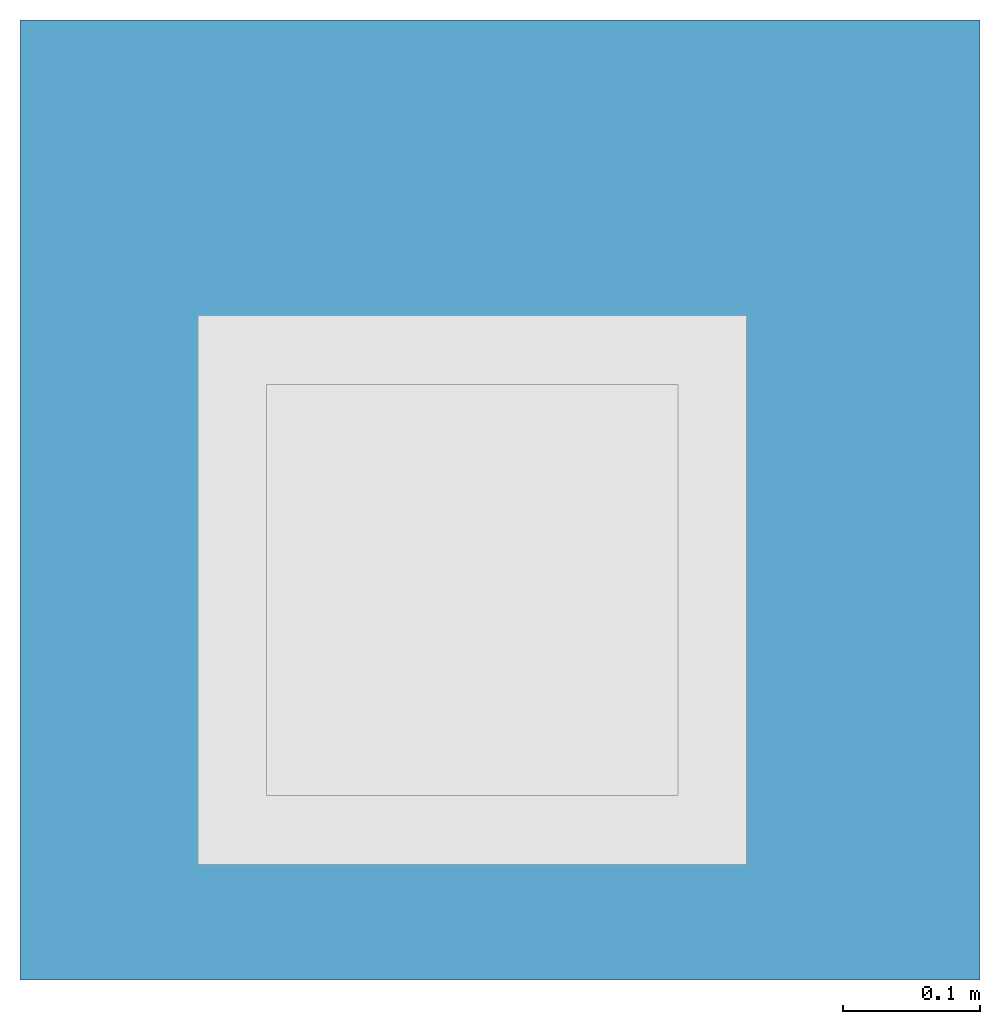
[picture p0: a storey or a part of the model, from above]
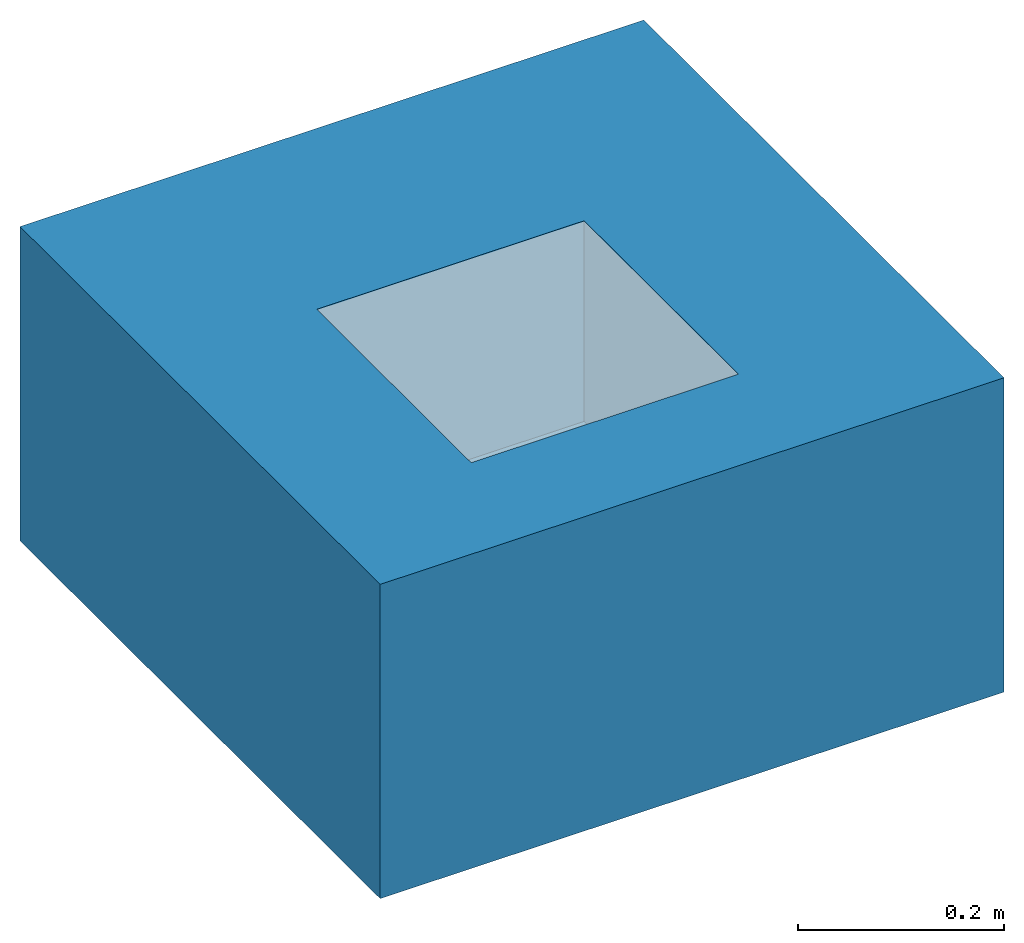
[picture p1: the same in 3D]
Properties of the parts of a building model (IFC2X3)

# File
Description: ViewDefinition [CoordinationView]
File name: Project Number
Time: 2014-10-13T17:47:48
Written by: The EXPRESS Data Manager Version 5.01.0100.02.64mod : 6 Jun 2012
Made in: 20130308_1515(x64) - Exporter 2014.0.2013.0308 - Default UI
Comment: STEP Physical File produced by: The EXPRESS Data Manager Version 5.01.0100.02.64mod : 6 Jun 2012 * Module: EDMstepFileFactory/EDMstandAlone * Creation date: Mon Oct 13 17:47:48 2014 * Host: IN-BLR-PC-0012 * Database: C:\Users\pponnur\AppData\Local\Temp\{98D3B113-D90C-4DA0-A6F4-5854EFEE299B}\ifc * Database version: 5507 * Database creation date: Mon Oct 13 17:47:47 2014 * Schema: IFC2X3 * Model: DataRepository.ifc * Model creation date: Mon Oct 13 17:47:48 2014 * Header model: DataRepository.ifc_HeaderModel * Header model creation date: Mon Oct 13 17:47:48 2014 * EDMuser: sdai-user * EDMgroup: sdai-group * License ID and type: 5605 : Permanent license. Expiry date: * EDMstepFileFactory options: 020000

# IfcProject, Project Number
LongName: Project Name; Phase: Project Status

# IfcSite, Default
RefLatitude: 42, 21, 30, 344238; RefLongitude: -71, -3, -35, -194702; RefElevation: 0 mm

# IfcBuilding
Pset_BuildingCommon - NumberOfStoreys: 1
Other - Client Name: Owner; Project Status: Project Status; Project Issue Date: Issue Date; Project Number: Project Number; Project Name: Project Name; Project Address: Enter address here

# IfcBuildingStorey, Level 1
LongName: Level 1; Elevation: 0 mm
Constraints - Elevation Base: Project Base Point; Elevation: 0 mm
Graphics - Symbol: Level Head - Circle: Level Head - Circle; Symbol at End 2 Default: yes; Symbol at End 1 Default: no; Color: 0; Line Pattern: Grid Line 1/2"; Line Weight: 1
Dimensions - Computation Height: 0 mm
Identity Data - Name: Level 1; Building Story: yes; Structural: no

# IfcFlowTerminal: 408061 Body / 408243 Top, ACO BD Gully 218 Telescopic - Thin Bed - Vertical Outlet with Location Flange - 300x300:408061 Body / 408243 Top:195708
In: Level 1
Material: Stainless Steel AISI 304, Rubber, Nitrile
Materials and Finishes - Material: Stainless Steel AISI 304
Construction - 408034 - 268 x 268mm - Mesh Grating - Slip Resistant - Stainless Steel 304: no; 408037 - 268 x 268mm - Ladder Grating - Slip Resistant - Stainless steel 304: no; 408035 - 268 x 268mm - Mesh Grating - Plain - Stainless Steel 304: no; 408222 - Silt Basket: yes; 408036 - 268 x 268mm - Quadrato Grating - Brushed - Stainless steel 304: no; 408045 - 268 x 268mm - Ladder Grating - Plain - Stainless Steel 304: no; 408039 - 268 x 268mm - Slot Cover - Plain - Stainless Steel 304: no; 408042 - 268 x 268mm - Volcano Grating - Slip Resistant - Stainless Steel 304: no; 408038 - 268 x 268mm - Ladder Grating - Plain - Stainless Steel 304: no; 408220 - Foul Air Trap & 408221 - Foul Air Trap Support Ring: yes; 408041 - 268 x 268mm - Arla Grating - Slip Resistant - Stainless Steel 304: no; 408040 - 268 x 268mm - HeelSafe Grating - Brushed - Stainless Steel 304: no
Mechanical - System Classification: Sanitary
Dimensions - Outlet Void Start: -238 mm; Floor Void End: -238 mm; FFL To Gully Top Height: 68 mm; Floor To Gully Height: 68 mm; Rasing Piece Height: 500 mm; Outlet Void End: -336 mm; Gully Outlet Radius: 55 mm; Gully Outlet Depth: 98 mm; Gully Outlet Diameter: 110 mm; Thin Bed Void Start: 0 mm; Thin Bed Void End: 2 mm
Other - Raising Piece Detail: no; 408209 - Raising Piece with Location Flange: no; Thin Bed Void: no; 110 mm Outlet: yes; 160 mm Outlet: no
Constraints - Level: Level: Level 1
Phasing - Phase Created: New Construction
Model Properties - Raising Piece Product Code 408209: NA; Product Code 408225: Friction Ring Installation Set - Nitrile; Product Code 408222: Silt Basket - Stainless Steel 304; Grating Product Code 408038: Load Class M125 (EN 1253) - Ladder Grating -Plain - Stainless steel 1.4301 (EN 10088) - 268 x 268 x 30mm; Grating Product Code 408042: Load Class M125 (EN 1253) - Volcano Grating - Slip Resistant - Stainless steel 1.4301 (EN 10088) - 268 x 268 x 30mm; Grating Product Code 408037: Load Class M125 (EN 1253) - Ladder Grating - Slip Resistant - Stainless steel 1.4301 (EN 10088) - 268 x 268 x 30mm; Grating Product Code 408041: Load Class L15 (EN 1253) - Arla Grating - Slip Resistant - Stainless steel 1.4301 (EN 10088) - 268 x 268 x 30mm; Grating Product Code 408034: Load Class L15 (EN 1253) - Mesh Grating - Slip Resistant - Stainless steel 1.4301 (EN 10088) - 268 x 268 x 30mm; Grating Product Code 408035: Load Class L15 (EN 1253) - Mesh Grating - Plain - Stainless steel 1.4301 (EN 10088) - 268 x 268 x 30mm; Grating Product Code 408039: Load Class M125 (EN 1253) - Slot Cover - Plain - Stainless steel 1.4301 (EN 10088) - 268 x 268 x 30mm; Grating Product Code 408045: Load Class C250 (EN 1253) - Ladder Grating - Plain - Stainless steel 1.4301 (EN 10088) - 268 x 268 x 30mm; Product Code 408221: Foul Air Trap Support Ring - Nitrile; Grating Product Code 408036: Load Class L15 (EN 1253) - Quadrato Grating - Brushed - Stainless steel 1.4301 (EN 10088) - 268 x 268 x 30mm; Product Code 408220: Foul Air Trap - Stainless Steel 304; Grating Product Code 408040: Load Class L15 (EN 1253) - Heelsafe Grating - Brushed - Stainless steel 1.4301 (EN 10088) - 268 x 268 x 30mm
Identity Data - Mark: 5; E-mail Sales: abdcommercial@aco.co.uk; Address: ACO Business Centre, Caxton Road, Bedford, MK41 0LF; Telephone: +44 (0)1462 816666; Fax: +44 (0)1462 851490; Manufacturer: ACO Building Drainage; Website: www.acobd.com; Watermarked By: www.acobd.com; Water Mark 2: This file is water marked and users are prohibited to reproduce, adapt, distribute this information; E-mail Technical: abdtechnical@aco.co.uk; Water Mark 1: This file is the property of ACO Technologies PLC; Water Marked With: BIM Manager Premium Suite
Pset_ManufacturerTypeInformation - Manufacturer: ACO Building Drainage
General - Foul Air Trap Seal Material: NBR; Foul Air Trap Seal Colour: Black; Gully Top Product Code: 408243; Outlet Diameter (mm): 110; Product Range: ACO Gully 218; Product Standard: EN 1253; Gully Recyclable: Fully recyclable; Gully Product Code: 408061; Load Class: A15 - C250 (EN 1253); Gully Colour: passivated stainless steel surface ( matt grey); Foul Air Trap Seal Recycled Material Content: 0%; Gully Product Description: ACO Gully 218 Telescopic Flange Type DN110 Vertical with Foul Air Trap; Maintenance guidelines: http://issuu.com/acobuildingdrainage/docs/120820112708-138bdc871b784edfa2b6b8197acfd881?e=0; Gully Flange Type: Location; Installation guidelines: http://issuu.com/acobuildingdrainage/docs/120820112708-138bdc871b784edfa2b6b8197acfd881?e=0; Flow Rate (l/s): 5.0 - 6.3 l/s; Gully top Grate size (mm): 300 x 300; Product Type: Point drainage; Gully Recycled Material Content: 20 - 30 %; Gully Top Size (mm): 242mm Diameter; NBS Specification: R11 ABOVE GROUND FOUL DRAINAGE SYSTEMS : Clause 315; Gully Top Product Description: ACO Gully 218 Telescopic Top for Thin Bed top or Tanked Flooring; Price: POA - contact ACO; Gully Material: Stainless Steel Grade 304 (EN 1253); Foul Air Trap Seal Recyclable: Fully recyclable

# IfcOpeningElement: Recess
In: Level 1
Dimensions - Thickness: 372.8 mm; Area: 5.27432 ft2; Perimeter: 2800 mm; Volume: 5.66169 ft3
Phasing - Phase Created: New Construction
Structural - Structural: no; Enable Analytical Model: no
Constraints - Room Bounding: yes; Level: Level: Level 1; Height Offset From Level: 0 mm; Related to Mass: no
Identity Data - Assembly Code: B1010; Assembly Description: Floor Construction
Graphics - Coarse Scale Fill Color: 0
Analytical Properties - Absorptance: 0.7; Thermal Resistance (R): 0.641509; Thermal mass: 53301.1; Heat Transfer Coefficient (U): 1.55882; Roughness: 3
Construction - Function: Interior; Default Thickness: 372.8 mm

# IfcSlab: Floor:Generic - 12", Floor:Generic - 12":184145
In: Level 1
PredefinedType: FLOOR; Material: Plywood, Sheathing 68 mm, Default Floor 304.8 mm
Dimensions - Thickness: 372.8 mm; Area: 5.27432 ft2; Perimeter: 2800 mm; Volume: 5.66169 ft3
Phasing - Phase Created: New Construction
Structural - Structural: no; Enable Analytical Model: no
Constraints - Room Bounding: yes; Level: Level: Level 1; Height Offset From Level: 0 mm; Related to Mass: no
Pset_SlabCommon - Reference: Generic - 12"; IsExternal: no; LoadBearing: yes; ThermalTransmittance: 1.55882 kg/K/s3
Identity Data - Assembly Code: B1010; Assembly Description: Floor Construction
Graphics - Coarse Scale Fill Color: 0
Analytical Properties - Absorptance: 0.7; Thermal Resistance (R): 0.641509; Thermal mass: 53301.1; Heat Transfer Coefficient (U): 1.55882; Roughness: 3
Construction - Function: Interior; Default Thickness: 372.8 mm
